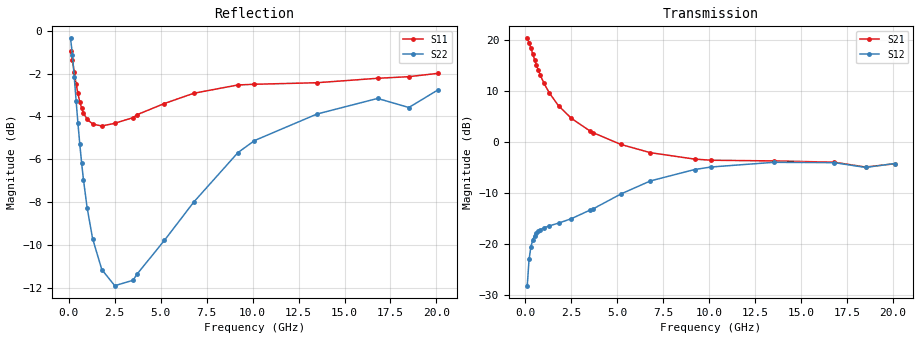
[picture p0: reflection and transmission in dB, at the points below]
!  Infineon Technologies AG
! BFR380L3 , PF131585-7, No.6, Th 09.10.01, soldered on pcb-board, measured with PP GSG850
!  Vce=0.75 V,  Ic=3.0 mA
! Common Emitter S-Parameters:  15. November 2001
#  GHz  S  MA  R  50
! f  S11  S21  S12  S22
! GHz  Mag  Ang  Mag  Ang  Mag  Ang  Mag  Ang
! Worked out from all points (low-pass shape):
!   201 points, 100 MHz to 20.1 GHz, reference 50 ohm
!   highest |S21| = 20.32 dB at 100 MHz (marker M1); lowest = -4.9 dB at 18.5 GHz (marker M2)
!   |S21| within 3 dB of the highest: start of sweep to 396.5 MHz
!   lowest |S11| = -4.4 dB at 1.8 GHz (marker M3), VSWR 3.99, Z = 12.6 - j2.31 ohm
!   |S11| at or under -10 dB: nowhere
!   |S22| runs from -12.0 to -0.4 dB; largest |S21 - S12| = 10
!   S11 on the Smith chart (normalised r, x): 100 MHz: 1.04, -4.13; 400 MHz: 0.30, -1.04; 1 GHz: 0.26, -0.33; 3.7 GHz: 0.24, +0.29; 9.2 GHz: 0.32, +1.08; 20.1 GHz: 0.97, +2.59
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0.1  0.8967 -25.7  10.37 163.1  0.03907 75.4  0.9603 -16.0
0.2  0.855 -48.8  9.395 148.2  0.07104 63.4  0.8788 -30.0
0.3  0.8001 -68.8  8.325 136.0  0.09404 54.2  0.7798 -41.4
0.4  0.7505 -85.3  7.31 126.0  0.11 47.2  0.6874 -50.3
0.5  0.714 -99.3  6.416 117.9  0.1208 42.1  0.6085 -57.3
0.6  0.6817 -110.6  5.677 111.4  0.1285 38.5  0.5442 -63.0
0.7  0.6606 -120.3  5.076 105.7  0.1339 35.8  0.4916 -67.7
0.8  0.6423 -128.7  4.568 100.9  0.138 33.9  0.4491 -71.6
1  0.6216 -141.8  3.8 93.0  0.1442 31.5  0.386 -78.1
1.3  0.6056 -156.8  3.029 83.4  0.1507 30.3  0.3267 -85.9
1.8  0.5993 -174.4  2.268 70.8  0.1604 31.5  0.2767 -96.4
2.5  0.6081 167.8  1.705 56.8  0.1772 35.3  0.2538 -110.2
3.5  0.6269 148.6  1.287 40.7  0.2146 40.6  0.2613 -129.0
3.7  0.6364 145.8  1.23 38.1  0.2221 41.0  0.2696 -133.4
5.2  0.6763 123.6  0.9456 20.6  0.3098 40.5  0.3237 -160.2
6.8  0.7147 104.0  0.7858 8.5  0.4156 33.4  0.398 171.8
9.2  0.7473 82.6  0.68 -2.6  0.5373 16.8  0.5192 139.6
10.1  0.7501 76.2  0.6629 -6.1  0.5689 10.6  0.554 129.0
13.5  0.7564 58.5  0.6526 -19.7  0.6322 -11.5  0.6391 97.1
16.8  0.7747 46.8  0.6343 -31.8  0.6278 -27.4  0.6951 75.2
18.5  0.7814 45.0  0.5681 -39.5  0.5632 -35.8  0.662 69.7
20.1  0.7958 37.9  0.6128 -43.4  0.6157 -40.6  0.7285 59.0
